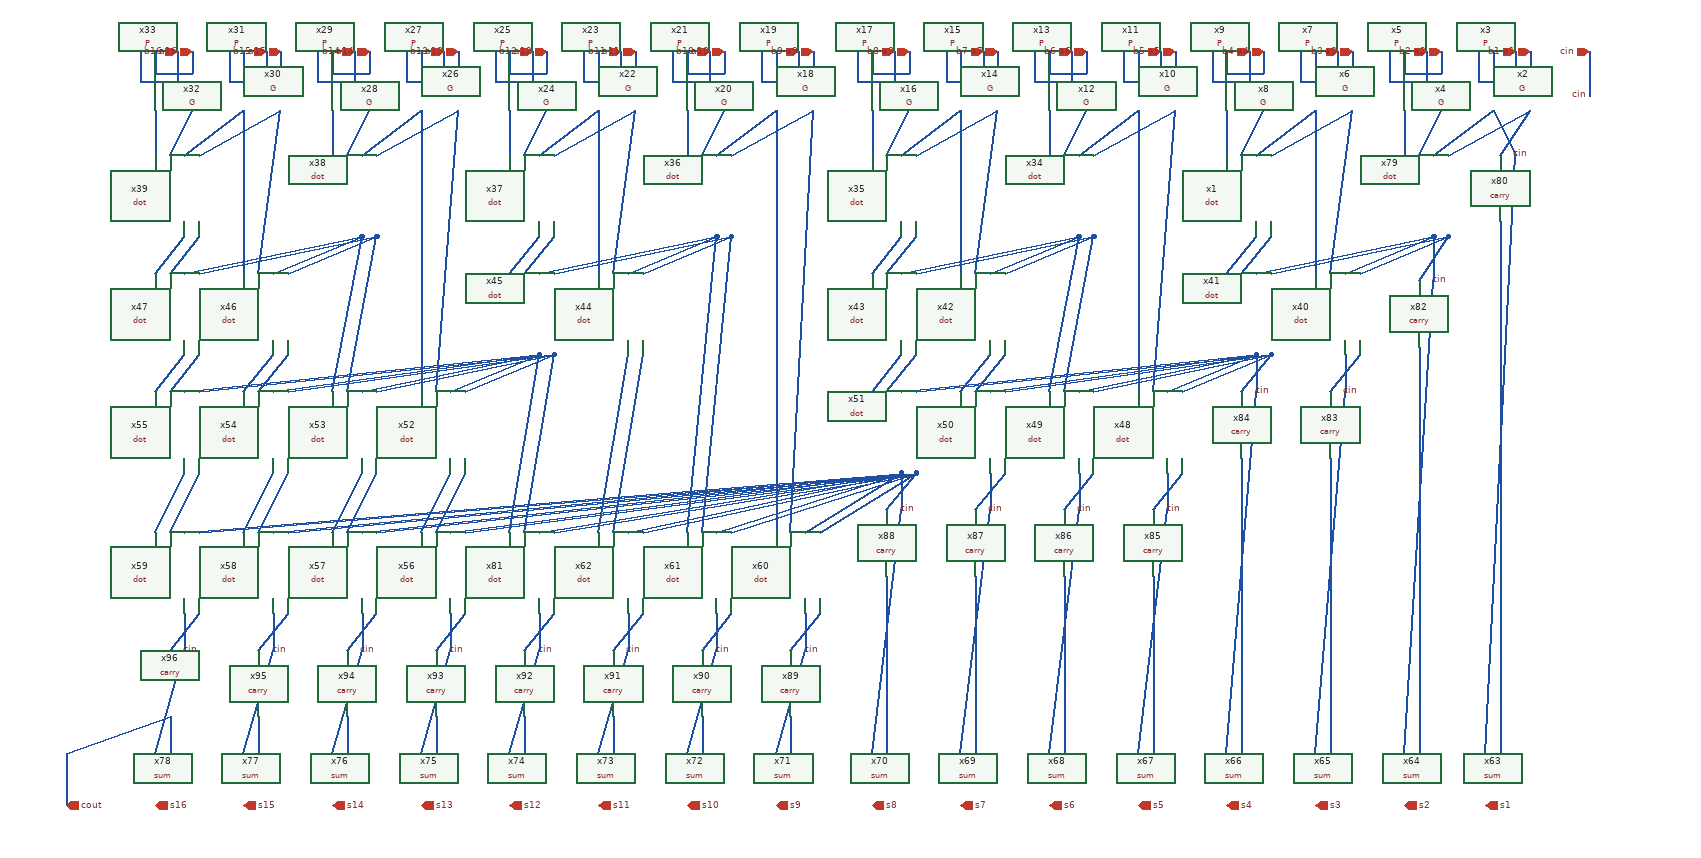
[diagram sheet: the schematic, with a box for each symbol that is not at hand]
v {xschem version=3.4.6 file_version=1.2}
G {}
K {}
V {}
S {}
E {}
N 1020 -110 1020 -50 {lab=cin}
N 940 -110 940 -80 {lab=a1}
N 890 -80 940 -80 {lab=a1}
N 890 -110 890 -80 {lab=a1}
N 920 -110 920 -70 {lab=b1}
N 870 -70 920 -70 {lab=b1}
N 870 -110 870 -70 {lab=b1}
N 820 -110 820 -80 {lab=a2}
N 770 -80 820 -80 {lab=a2}
N 770 -110 770 -80 {lab=a2}
N 800 -110 800 -70 {lab=b2}
N 750 -70 800 -70 {lab=b2}
N 750 -110 750 -70 {lab=b2}
N 700 -110 700 -80 {lab=a3}
N 650 -80 700 -80 {lab=a3}
N 650 -110 650 -80 {lab=a3}
N 680 -110 680 -70 {lab=b3}
N 630 -70 680 -70 {lab=b3}
N 630 -110 630 -70 {lab=b3}
N 580 -110 580 -80 {lab=a4}
N 530 -80 580 -80 {lab=a4}
N 530 -110 530 -80 {lab=a4}
N 560 -110 560 -70 {lab=b4}
N 510 -70 560 -70 {lab=b4}
N 510 -110 510 -70 {lab=b4}
N 460 -110 460 -80 {lab=a5}
N 410 -80 460 -80 {lab=a5}
N 410 -110 410 -80 {lab=a5}
N 440 -110 440 -70 {lab=b5}
N 390 -70 440 -70 {lab=b5}
N 390 -110 390 -70 {lab=b5}
N 340 -110 340 -80 {lab=a6}
N 290 -80 340 -80 {lab=a6}
N 290 -110 290 -80 {lab=a6}
N 320 -110 320 -70 {lab=b6}
N 270 -70 320 -70 {lab=b6}
N 270 -110 270 -70 {lab=b6}
N 220 -110 220 -80 {lab=a7}
N 170 -80 220 -80 {lab=a7}
N 170 -110 170 -80 {lab=a7}
N 200 -110 200 -70 {lab=b7}
N 150 -70 200 -70 {lab=b7}
N 150 -110 150 -70 {lab=b7}
N 100 -110 100 -80 {lab=a8}
N 50 -80 100 -80 {lab=a8}
N 50 -110 50 -80 {lab=a8}
N 80 -110 80 -70 {lab=b8}
N 30 -70 80 -70 {lab=b8}
N 30 -110 30 -70 {lab=b8}
N -30 -110 -30 -80 {lab=a9}
N -80 -80 -30 -80 {lab=a9}
N -80 -110 -80 -80 {lab=a9}
N -50 -110 -50 -70 {lab=b9}
N -100 -70 -50 -70 {lab=b9}
N -100 -110 -100 -70 {lab=b9}
N -150 -110 -150 -80 {lab=a10}
N -200 -80 -150 -80 {lab=a10}
N -200 -110 -200 -80 {lab=a10}
N -170 -110 -170 -70 {lab=b10}
N -220 -70 -170 -70 {lab=b10}
N -220 -110 -220 -70 {lab=b10}
N -270 -110 -270 -80 {lab=a11}
N -320 -80 -270 -80 {lab=a11}
N -320 -110 -320 -80 {lab=a11}
N -290 -110 -290 -70 {lab=b11}
N -340 -70 -290 -70 {lab=b11}
N -340 -110 -340 -70 {lab=b11}
N -390 -110 -390 -80 {lab=a12}
N -440 -80 -390 -80 {lab=a12}
N -440 -110 -440 -80 {lab=a12}
N -410 -110 -410 -70 {lab=b12}
N -460 -70 -410 -70 {lab=b12}
N -460 -110 -460 -70 {lab=b12}
N -510 -110 -510 -80 {lab=a13}
N -560 -80 -510 -80 {lab=a13}
N -560 -110 -560 -80 {lab=a13}
N -530 -110 -530 -70 {lab=b13}
N -580 -70 -530 -70 {lab=b13}
N -580 -110 -580 -70 {lab=b13}
N -630 -110 -630 -80 {lab=a14}
N -680 -80 -630 -80 {lab=a14}
N -680 -110 -680 -80 {lab=a14}
N -650 -110 -650 -70 {lab=b14}
N -700 -70 -650 -70 {lab=b14}
N -700 -110 -700 -70 {lab=b14}
N -750 -110 -750 -80 {lab=a15}
N -800 -80 -750 -80 {lab=a15}
N -800 -110 -800 -80 {lab=a15}
N -770 -110 -770 -70 {lab=b15}
N -820 -70 -770 -70 {lab=b15}
N -820 -110 -820 -70 {lab=b15}
N -870 -110 -870 -80 {lab=a16}
N -920 -80 -870 -80 {lab=a16}
N -920 -110 -920 -80 {lab=a16}
N -890 -110 -890 -70 {lab=b16}
N -940 -70 -890 -70 {lab=b16}
N -940 -110 -940 -70 {lab=b16}
N -1040 840 -1040 910 {lab=cout}
N 770 -30 770 30 {lab=#net1}
N 790 30 820 -30 {lab=#net2}
N 810 30 890 -30 {lab=#net3}
N 830 30 940 -30 {lab=#net4}
N 530 -30 530 30 {lab=#net5}
N 550 30 580 -30 {lab=#net6}
N 570 30 650 -30 {lab=#net7}
N 590 30 700 -30 {lab=#net8}
N 290 -30 290 30 {lab=#net9}
N 310 30 340 -30 {lab=#net10}
N 330 30 410 -30 {lab=#net11}
N 350 30 460 -30 {lab=#net12}
N 50 -30 50 30 {lab=#net13}
N 70 30 100 -30 {lab=#net14}
N 90 30 170 -30 {lab=#net15}
N 110 30 220 -30 {lab=#net16}
N -200 -30 -200 30 {lab=#net17}
N -180 30 -150 -30 {lab=#net18}
N -160 30 -80 -30 {lab=#net19}
N -140 30 -30 -30 {lab=#net20}
N -440 -30 -440 30 {lab=#net21}
N -420 30 -390 -30 {lab=#net22}
N -400 30 -320 -30 {lab=#net23}
N -380 30 -270 -30 {lab=#net24}
N -680 -30 -680 30 {lab=#net25}
N -660 30 -630 -30 {lab=#net26}
N -640 30 -560 -30 {lab=#net27}
N -620 30 -510 -30 {lab=#net28}
N -920 -30 -920 30 {lab=#net29}
N -900 30 -870 -30 {lab=#net30}
N -880 30 -800 -30 {lab=#net31}
N -860 30 -750 -30 {lab=#net32}
N 650 -30 650 190 {lab=#net7}
N 670 190 700 -30 {lab=#net8}
N 690 190 810 140 {lab=#net33}
N 710 190 830 140 {lab=#net34}
N 530 190 570 140 {lab=#net35}
N 550 190 590 140 {lab=#net36}
N 570 190 810 140 {lab=#net33}
N 590 190 830 140 {lab=#net34}
N 170 -30 170 190 {lab=#net15}
N 190 190 220 -30 {lab=#net16}
N 210 190 330 140 {lab=#net37}
N 230 190 350 140 {lab=#net38}
N 50 190 90 140 {lab=#net39}
N 70 190 110 140 {lab=#net40}
N 90 190 330 140 {lab=#net37}
N 110 190 350 140 {lab=#net38}
N -320 -30 -320 190 {lab=#net23}
N -300 190 -270 -30 {lab=#net24}
N -280 190 -160 140 {lab=#net41}
N -260 190 -140 140 {lab=#net42}
N -440 190 -400 140 {lab=#net43}
N -420 190 -380 140 {lab=#net44}
N -400 190 -160 140 {lab=#net41}
N -380 190 -140 140 {lab=#net42}
N -800 -30 -800 190 {lab=#net31}
N -780 190 -750 -30 {lab=#net32}
N -760 190 -640 140 {lab=#net45}
N -740 190 -620 140 {lab=#net46}
N -920 190 -880 140 {lab=#net47}
N -900 190 -860 140 {lab=#net48}
N -880 190 -640 140 {lab=#net45}
N -860 190 -620 140 {lab=#net46}
N 470 350 590 300 {lab=#net49}
N 450 350 570 300 {lab=#net50}
N 350 350 590 300 {lab=#net49}
N 330 350 570 300 {lab=#net50}
N 230 350 590 300 {lab=#net49}
N 210 350 570 300 {lab=#net50}
N 110 350 590 300 {lab=#net49}
N 90 350 570 300 {lab=#net50}
N 410 -30 410 350 {lab=#net11}
N 430 350 460 -30 {lab=#net12}
N 290 350 330 140 {lab=#net37}
N 310 350 350 140 {lab=#net38}
N 170 350 210 300 {lab=#net51}
N 190 350 230 300 {lab=#net52}
N 50 350 90 300 {lab=#net53}
N 70 350 110 300 {lab=#net54}
N -500 350 -380 300 {lab=#net55}
N -520 350 -400 300 {lab=#net56}
N -620 350 -380 300 {lab=#net55}
N -640 350 -400 300 {lab=#net56}
N -740 350 -380 300 {lab=#net55}
N -760 350 -400 300 {lab=#net56}
N -860 350 -380 300 {lab=#net55}
N -880 350 -400 300 {lab=#net56}
N -560 -30 -560 350 {lab=#net27}
N -540 350 -510 -30 {lab=#net28}
N -680 350 -640 140 {lab=#net45}
N -660 350 -620 140 {lab=#net46}
N -800 350 -760 300 {lab=#net57}
N -780 350 -740 300 {lab=#net58}
N -920 350 -880 300 {lab=#net59}
N -900 350 -860 300 {lab=#net60}
N -40 540 90 460 {lab=#net61}
N -20 540 110 460 {lab=#net62}
N -880 540 90 460 {lab=#net61}
N -760 540 90 460 {lab=#net61}
N -640 540 90 460 {lab=#net61}
N -520 540 90 460 {lab=#net61}
N -400 540 90 460 {lab=#net61}
N -280 540 90 460 {lab=#net61}
N -160 540 90 460 {lab=#net61}
N -860 540 110 460 {lab=#net62}
N -740 540 110 460 {lab=#net62}
N -620 540 110 460 {lab=#net62}
N -500 540 110 460 {lab=#net62}
N -380 540 110 460 {lab=#net62}
N -260 540 110 460 {lab=#net62}
N -140 540 110 460 {lab=#net62}
N -80 -30 -80 540 {lab=#net19}
N -60 540 -30 -30 {lab=#net20}
N -200 540 -160 140 {lab=#net41}
N -180 540 -140 140 {lab=#net42}
N -320 540 -280 300 {lab=#net63}
N -300 540 -260 300 {lab=#net64}
N -440 540 -400 300 {lab=#net56}
N -420 540 -380 300 {lab=#net55}
N -560 540 -520 460 {lab=#net65}
N -540 540 -500 460 {lab=#net66}
N -680 540 -640 460 {lab=#net67}
N -660 540 -620 460 {lab=#net68}
N -800 540 -760 460 {lab=#net69}
N -780 540 -740 460 {lab=#net70}
N -920 540 -880 460 {lab=#net71}
N -900 540 -860 460 {lab=#net72}
N 900 30 940 -30 {lab=#net4}
N 890 -30 920 30 {lab=#net3}
N 790 200 830 140 {lab=#net34}
N 810 140 810 200 {lab=#net33}
N 670 350 710 300 {lab=#net73}
N 690 300 690 350 {lab=#net74}
N 570 300 570 350 {lab=#net50}
N 550 350 590 300 {lab=#net49}
N 450 460 450 510 {lab=#net75}
N 430 510 470 460 {lab=#net76}
N 330 460 330 510 {lab=#net77}
N 310 510 350 460 {lab=#net78}
N 210 460 210 510 {lab=#net79}
N 190 510 230 460 {lab=#net80}
N 90 460 90 510 {lab=#net61}
N 70 510 110 460 {lab=#net62}
N -40 650 -40 700 {lab=#net81}
N -60 700 -20 650 {lab=#net82}
N -160 650 -160 700 {lab=#net83}
N -180 700 -140 650 {lab=#net84}
N -280 650 -280 700 {lab=#net85}
N -300 700 -260 650 {lab=#net86}
N -400 650 -400 700 {lab=#net87}
N -420 700 -380 650 {lab=#net88}
N -520 650 -520 700 {lab=#net89}
N -540 700 -500 650 {lab=#net90}
N -640 650 -640 700 {lab=#net91}
N -660 700 -620 650 {lab=#net92}
N -760 650 -760 700 {lab=#net93}
N -780 700 -740 650 {lab=#net94}
N -880 650 -880 700 {lab=#net95}
N -900 700 -860 650 {lab=#net96}
N 70 600 70 840 {lab=#net97}
N 190 600 190 840 {lab=#net98}
N 310 610 310 840 {lab=#net99}
N 430 610 430 840 {lab=#net100}
N 550 450 550 840 {lab=#net101}
N 670 450 670 840 {lab=#net102}
N 790 300 790 840 {lab=#net103}
N 900 130 900 840 {lab=#net104}
N -60 800 -60 840 {lab=#net105}
N -180 800 -180 840 {lab=#net106}
N -300 800 -300 840 {lab=#net107}
N -420 800 -420 840 {lab=#net108}
N -540 800 -540 840 {lab=#net109}
N -900 800 -900 840 {lab=cout}
N -780 800 -780 840 {lab=#net110}
N -660 800 -660 840 {lab=#net111}
N -920 840 -880 700 {lab=#net95}
N -800 840 -760 700 {lab=#net93}
N -680 840 -640 700 {lab=#net91}
N -560 840 -520 700 {lab=#net89}
N -440 840 -400 700 {lab=#net87}
N -320 840 -280 700 {lab=#net85}
N -200 840 -160 700 {lab=#net83}
N -80 840 -40 700 {lab=#net81}
N 50 840 90 510 {lab=#net61}
N 170 840 210 510 {lab=#net79}
N 290 840 330 510 {lab=#net77}
N 410 840 450 510 {lab=#net75}
N 530 840 570 350 {lab=#net50}
N 650 840 690 350 {lab=#net74}
N 770 840 810 200 {lab=#net33}
N 880 840 920 30 {lab=#net3}
N 670 440 670 450 {lab=#net102}
N 550 440 550 450 {lab=#net101}
N 790 290 790 300 {lab=#net103}
N 900 120 900 130 {lab=#net104}
N 430 600 430 610 {lab=#net100}
N 310 600 310 610 {lab=#net99}
N -60 790 -60 800 {lab=#net105}
N -180 790 -180 800 {lab=#net106}
N -300 790 -300 800 {lab=#net107}
N -420 790 -420 800 {lab=#net108}
N -540 790 -540 800 {lab=#net109}
N -660 790 -660 800 {lab=#net111}
N -780 790 -780 800 {lab=#net110}
N -900 790 -900 800 {lab=cout}
N -1040 840 -900 790 {lab=cout}
C {G.sym} 930 -70 1 0 {name=x2}
C {P.sym} 880 -70 1 0 {name=x3}
C {G.sym} 810 -70 1 0 {name=x4}
C {P.sym} 760 -70 1 0 {name=x5}
C {G.sym} 690 -70 1 0 {name=x6}
C {P.sym} 640 -70 1 0 {name=x7}
C {G.sym} 570 -70 1 0 {name=x8}
C {P.sym} 520 -70 1 0 {name=x9}
C {G.sym} 450 -70 1 0 {name=x10}
C {P.sym} 400 -70 1 0 {name=x11}
C {G.sym} 330 -70 1 0 {name=x12}
C {P.sym} 280 -70 1 0 {name=x13}
C {G.sym} 210 -70 1 0 {name=x14}
C {P.sym} 160 -70 1 0 {name=x15}
C {G.sym} 90 -70 1 0 {name=x16}
C {P.sym} 40 -70 1 0 {name=x17}
C {G.sym} -40 -70 1 0 {name=x18}
C {P.sym} -90 -70 1 0 {name=x19}
C {G.sym} -160 -70 1 0 {name=x20}
C {P.sym} -210 -70 1 0 {name=x21}
C {G.sym} -280 -70 1 0 {name=x22}
C {P.sym} -330 -70 1 0 {name=x23}
C {G.sym} -400 -70 1 0 {name=x24}
C {P.sym} -450 -70 1 0 {name=x25}
C {G.sym} -520 -70 1 0 {name=x26}
C {P.sym} -570 -70 1 0 {name=x27}
C {G.sym} -640 -70 1 0 {name=x28}
C {P.sym} -690 -70 1 0 {name=x29}
C {G.sym} -760 -70 1 0 {name=x30}
C {P.sym} -810 -70 1 0 {name=x31}
C {G.sym} -880 -70 1 0 {name=x32}
C {P.sym} -930 -70 1 0 {name=x33}
C {sum.sym} 890 870 3 1 {name=x63}
C {sum.sym} 780 870 3 1 {name=x64}
C {sum.sym} 660 870 3 1 {name=x65}
C {sum.sym} 540 870 3 1 {name=x66}
C {sum.sym} 420 870 3 1 {name=x67}
C {sum.sym} 300 870 3 1 {name=x68}
C {sum.sym} 180 870 3 1 {name=x69}
C {sum.sym} 60 870 3 1 {name=x70}
C {sum.sym} -70 870 3 1 {name=x71}
C {sum.sym} -190 870 3 1 {name=x72}
C {sum.sym} -310 870 3 1 {name=x73}
C {sum.sym} -430 870 3 1 {name=x74}
C {sum.sym} -550 870 3 1 {name=x75}
C {sum.sym} -670 870 3 1 {name=x76}
C {sum.sym} -790 870 3 1 {name=x77}
C {sum.sym} -910 870 3 1 {name=x78}
C {ipin.sym} -890 -110 1 0 {name=p3 lab=b16}
C {ipin.sym} -870 -110 1 0 {name=p4 lab=a16}
C {ipin.sym} -770 -110 1 0 {name=p7 lab=b15}
C {ipin.sym} -750 -110 1 0 {name=p8 lab=a15}
C {ipin.sym} -650 -110 1 0 {name=p11 lab=b14}
C {ipin.sym} -630 -110 1 0 {name=p12 lab=a14}
C {ipin.sym} -530 -110 1 0 {name=p15 lab=b13}
C {ipin.sym} -510 -110 1 0 {name=p16 lab=a13}
C {ipin.sym} -410 -110 1 0 {name=p19 lab=b12}
C {ipin.sym} -390 -110 1 0 {name=p20 lab=a12}
C {ipin.sym} -290 -110 1 0 {name=p23 lab=b11}
C {ipin.sym} -270 -110 1 0 {name=p24 lab=a11}
C {ipin.sym} -170 -110 1 0 {name=p27 lab=b10}
C {ipin.sym} -150 -110 1 0 {name=p28 lab=a10}
C {ipin.sym} -50 -110 1 0 {name=p31 lab=b9}
C {ipin.sym} -30 -110 1 0 {name=p32 lab=a9}
C {ipin.sym} 80 -110 1 0 {name=p35 lab=b8}
C {ipin.sym} 100 -110 1 0 {name=p36 lab=a8}
C {ipin.sym} 200 -110 1 0 {name=p39 lab=b7}
C {ipin.sym} 220 -110 1 0 {name=p40 lab=a7}
C {ipin.sym} 320 -110 1 0 {name=p43 lab=b6}
C {ipin.sym} 340 -110 1 0 {name=p44 lab=a6}
C {ipin.sym} 440 -110 1 0 {name=p47 lab=b5}
C {ipin.sym} 460 -110 1 0 {name=p48 lab=a5}
C {ipin.sym} 560 -110 1 0 {name=p51 lab=b4}
C {ipin.sym} 580 -110 1 0 {name=p52 lab=a4}
C {ipin.sym} 680 -110 1 0 {name=p55 lab=b3}
C {ipin.sym} 700 -110 1 0 {name=p56 lab=a3}
C {ipin.sym} 800 -110 1 0 {name=p59 lab=b2}
C {ipin.sym} 820 -110 1 0 {name=p60 lab=a2}
C {ipin.sym} 920 -110 1 0 {name=p63 lab=b1}
C {ipin.sym} 940 -110 1 0 {name=p64 lab=a1}
C {ipin.sym} 1020 -110 1 0 {name=p65 lab=cin}
C {opin.sym} 880 910 1 0 {name=p1 lab=s1}
C {opin.sym} 770 910 1 0 {name=p2 lab=s2}
C {opin.sym} 650 910 1 0 {name=p5 lab=s3}
C {opin.sym} 530 910 1 0 {name=p6 lab=s4}
C {opin.sym} 410 910 1 0 {name=p9 lab=s5}
C {opin.sym} 290 910 1 0 {name=p10 lab=s6}
C {opin.sym} 170 910 1 0 {name=p13 lab=s7}
C {opin.sym} 50 910 1 0 {name=p14 lab=s8}
C {opin.sym} -80 910 1 0 {name=p17 lab=s9}
C {opin.sym} -200 910 1 0 {name=p18 lab=s10}
C {opin.sym} -320 910 1 0 {name=p21 lab=s11}
C {opin.sym} -440 910 1 0 {name=p22 lab=s12}
C {opin.sym} -560 910 1 0 {name=p25 lab=s13}
C {opin.sym} -680 910 1 0 {name=p26 lab=s14}
C {opin.sym} -800 910 1 0 {name=p29 lab=s15}
C {opin.sym} -920 910 1 0 {name=p30 lab=s16}
C {opin.sym} -1040 910 1 0 {name=p33 lab=cout}
C {dot.sym} 800 90 1 0 {name=x79}
C {carry.sym} 920 80 3 1 {name=x80}
C {dot.sym} 560 90 1 0 {name=x1}
C {dot.sym} 320 90 1 0 {name=x34}
C {dot.sym} 80 90 1 0 {name=x35}
C {dot.sym} -170 90 1 0 {name=x36}
C {dot.sym} -410 90 1 0 {name=x37}
C {dot.sym} -650 90 1 0 {name=x38}
C {dot.sym} -890 90 1 0 {name=x39}
C {dot.sym} 680 250 1 0 {name=x40}
C {dot.sym} 560 250 1 0 {name=x41}
C {dot.sym} 200 250 1 0 {name=x42}
C {dot.sym} 80 250 1 0 {name=x43}
C {dot.sym} -290 250 1 0 {name=x44}
C {dot.sym} -410 250 1 0 {name=x45}
C {dot.sym} -770 250 1 0 {name=x46}
C {dot.sym} -890 250 1 0 {name=x47}
C {dot.sym} 440 410 1 0 {name=x48}
C {dot.sym} 320 410 1 0 {name=x49}
C {dot.sym} 200 410 1 0 {name=x50}
C {dot.sym} 80 410 1 0 {name=x51}
C {dot.sym} -530 410 1 0 {name=x52}
C {dot.sym} -650 410 1 0 {name=x53}
C {dot.sym} -770 410 1 0 {name=x54}
C {dot.sym} -890 410 1 0 {name=x55}
C {dot.sym} -530 600 1 0 {name=x56}
C {dot.sym} -650 600 1 0 {name=x57}
C {dot.sym} -770 600 1 0 {name=x58}
C {dot.sym} -890 600 1 0 {name=x59}
C {dot.sym} -50 600 1 0 {name=x60}
C {dot.sym} -170 600 1 0 {name=x61}
C {dot.sym} -290 600 1 0 {name=x62}
C {dot.sym} -410 600 1 0 {name=x81}
C {carry.sym} 810 250 3 1 {name=x82}
C {carry.sym} 690 400 3 1 {name=x83}
C {carry.sym} 570 400 3 1 {name=x84}
C {carry.sym} 450 560 3 1 {name=x85}
C {carry.sym} 330 560 3 1 {name=x86}
C {carry.sym} 210 560 3 1 {name=x87}
C {carry.sym} 90 560 3 1 {name=x88}
C {carry.sym} -40 750 3 1 {name=x89}
C {carry.sym} -160 750 3 1 {name=x90}
C {carry.sym} -280 750 3 1 {name=x91}
C {carry.sym} -400 750 3 1 {name=x92}
C {carry.sym} -520 750 3 1 {name=x93}
C {carry.sym} -640 750 3 1 {name=x94}
C {carry.sym} -760 750 3 1 {name=x95}
C {carry.sym} -880 750 3 1 {name=x96}
C {lab_pin.sym} -860 700 1 0 {name=p34 sig_type=std_logic lab=cin}
C {lab_pin.sym} -740 700 1 0 {name=p37 sig_type=std_logic lab=cin}
C {lab_pin.sym} -620 700 1 0 {name=p38 sig_type=std_logic lab=cin}
C {lab_pin.sym} -500 700 1 0 {name=p41 sig_type=std_logic lab=cin}
C {lab_pin.sym} -380 700 1 0 {name=p42 sig_type=std_logic lab=cin}
C {lab_pin.sym} -260 700 1 0 {name=p45 sig_type=std_logic lab=cin}
C {lab_pin.sym} -140 700 1 0 {name=p46 sig_type=std_logic lab=cin}
C {lab_pin.sym} -20 700 1 0 {name=p49 sig_type=std_logic lab=cin}
C {lab_pin.sym} 110 510 1 0 {name=p50 sig_type=std_logic lab=cin}
C {lab_pin.sym} 230 510 1 0 {name=p53 sig_type=std_logic lab=cin}
C {lab_pin.sym} 350 510 1 0 {name=p54 sig_type=std_logic lab=cin}
C {lab_pin.sym} 470 510 1 0 {name=p57 sig_type=std_logic lab=cin}
C {lab_pin.sym} 590 350 1 0 {name=p58 sig_type=std_logic lab=cin}
C {lab_pin.sym} 710 350 1 0 {name=p61 sig_type=std_logic lab=cin}
C {lab_pin.sym} 830 200 1 0 {name=p62 sig_type=std_logic lab=cin}
C {lab_pin.sym} 940 30 1 0 {name=p66 sig_type=std_logic lab=cin}
C {lab_pin.sym} 1020 -50 1 1 {name=p67 sig_type=std_logic lab=cin}
